
SITE pad
    SYMMETRY x y r90 ;
    CLASS pad ;
    SIZE 0.005 BY 199.500 ;
END pad 

SITE corner
    SYMMETRY x y r90 ;
    CLASS pad ;
    SIZE 199.500 BY 199.500 ;
END corner

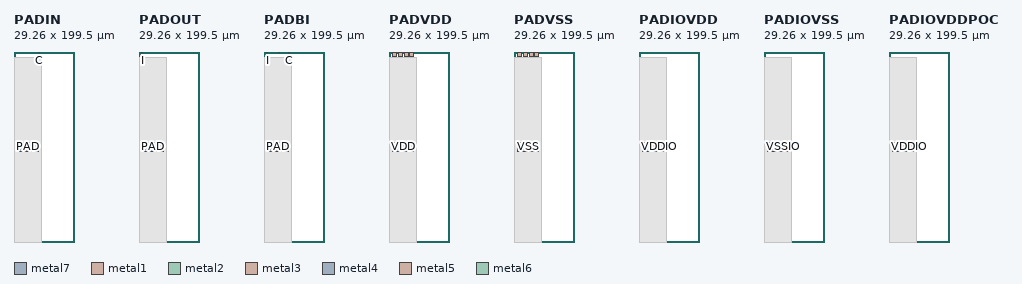
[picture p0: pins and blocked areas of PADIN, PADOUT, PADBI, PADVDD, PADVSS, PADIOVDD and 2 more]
MACRO PADIN
    CLASS PAD ;
    FOREIGN PADIN 0.000 0.000  ;
    ORIGIN 0.000 0.000 ;
    SIZE 29.260 BY 199.500 ;
    SYMMETRY x y r90 ;
    SITE pad ;
    PIN PAD
        DIRECTION INPUT ;
        PORT
        LAYER metal7 ;
        RECT  4.000 95 26.000 105 ;
        END
    END PAD
    PIN C
        DIRECTION OUTPUT ;
        PORT
        LAYER metal1 ;
        RECT  26 199.000 27 199.500 ;
        LAYER metal2 ;
        RECT  26 199.000 27 199.500 ;
        LAYER metal3 ;
        RECT  26 199.000 27 199.500 ;
        LAYER metal4 ;
        RECT  26 199.000 27 199.500 ;
        LAYER metal5 ;
        RECT  26 199.000 27 199.500 ;
        END
    END C
    OBS
        LAYER metal1 ;
        RECT  0.000 0.000 29.260 194.000 ;
        LAYER via1 ;
        RECT  0.000 0.000 29.260 194.000 ;
        LAYER metal2 ;
        RECT  0.000 0.000 29.260 194.000 ;
        LAYER via2 ;
        RECT  0.000 0.000 29.260 194.000 ;
        LAYER metal3 ;
        RECT  0.000 0.000 29.260 194.000 ;
        LAYER via3 ;
        RECT  0.000 0.000 29.260 194.000 ;
        LAYER metal4 ;
        RECT  0.000 0.000 29.260 194.000 ;
        LAYER via4 ;
        RECT  0.000 0.000 29.260 194.000 ;
        LAYER metal5 ;
        RECT  0.000 0.000 29.260 194.000 ;
        LAYER via5 ;
        RECT  0.000 0.000 29.260 194.000 ;
        LAYER metal6 ;
        RECT  0.000 0.000 29.260 194.000 ;
        LAYER via6 ;
        RECT  0.000 0.000 29.260 194.000 ;
    END
END PADIN

MACRO PADOUT
    CLASS PAD ;
    FOREIGN PADOUT 0.000 0.000  ;
    ORIGIN 0.000 0.000 ;
    SIZE 29.260 BY 199.500 ;
    SYMMETRY x y r90 ;
    SITE pad ;
    PIN PAD
        DIRECTION INOUT ;
        PORT
        LAYER metal7 ;
        RECT  4.000 95 26.000 105 ;
        END
    END PAD

    PIN I
        DIRECTION INPUT ;
        PORT
        LAYER metal1 ;
        RECT  3 199.000 4 199.500 ;
        LAYER metal2 ;
        RECT  3 199.000 4 199.500 ;
        LAYER metal3 ;
        RECT  3 199.000 4 199.500 ;
        LAYER metal4 ;
        RECT  3 199.000 4 199.500 ;
        LAYER metal5 ;
        RECT  3 199.000 4 199.500 ;
        LAYER metal6 ;
        RECT  3 199.000 4 199.500 ;
        END
    END I
    OBS
        LAYER metal1 ;
        RECT  0.000 0.000 29.260 194.000 ;
        LAYER via1 ;
        RECT  0.000 0.000 29.260 194.000 ;
        LAYER metal2 ;
        RECT  0.000 0.000 29.260 194.000 ;
        LAYER via2 ;
        RECT  0.000 0.000 29.260 194.000 ;
        LAYER metal3 ;
        RECT  0.000 0.000 29.260 194.000 ;
        LAYER via3 ;
        RECT  0.000 0.000 29.260 194.000 ;
        LAYER metal4 ;
        RECT  0.000 0.000 29.260 194.000 ;
        LAYER via4 ;
        RECT  0.000 0.000 29.260 194.000 ;
        LAYER metal5 ;
        RECT  0.000 0.000 29.260 194.000 ;
        LAYER via5 ;
        RECT  0.000 0.000 29.260 194.000 ;
        LAYER metal6 ;
        RECT  0.000 0.000 29.260 194.000 ;
        LAYER via6 ;
        RECT  0.000 0.000 29.260 194.000 ;
    END
END PADOUT

MACRO PADBI
    CLASS PAD ;
    FOREIGN PADBI 0.000 0.000  ;
    ORIGIN 0.000 0.000 ;
    SIZE 29.260 BY 199.500 ;
    SYMMETRY x y r90 ;
    SITE pad ;
    PIN PAD
        DIRECTION INOUT ;
        PORT
        LAYER metal7 ;
        RECT  4.000 95 26.000 105 ;
        END
    END PAD
    PIN C
        DIRECTION OUTPUT ;
        PORT
        LAYER metal1 ;
        RECT  26 199.000 27 199.500 ;
        LAYER metal2 ;
        RECT  26 199.000 27 199.500 ;
        LAYER metal3 ;
        RECT  26 199.000 27 199.500 ;
        LAYER metal4 ;
        RECT  26 199.000 27 199.500 ;
        LAYER metal5 ;
        RECT  26 199.000 27 199.500 ;
        LAYER metal6 ;
        RECT  26 199.000 27 199.500 ;
        END
    END C

    PIN OEN
        DIRECTION INPUT ;
        PORT
        LAYER metal1 ;
        RECT  15 199.090 16 199.500 ;
        LAYER metal2 ;
        RECT  15 199.000 16 199.500 ;
        LAYER metal3 ;
        RECT  15 199.000 16 199.500 ;
        LAYER metal4 ;
        RECT  15 199.000 16 199.500 ;
        LAYER metal5 ;
        RECT  15 199.000 16 199.500 ;
        LAYER metal6 ;
        RECT  15 199.000 16 199.500 ;
        END
    END OEN

    PIN I
        DIRECTION INPUT ;
        PORT
        LAYER metal1 ;
        RECT  3 199.000 4 199.500 ;
        LAYER metal2 ;
        RECT  3 199.000 4 199.500 ;
        LAYER metal3 ;
        RECT  3 199.000 4 199.500 ;
        LAYER metal4 ;
        RECT  3 199.000 4 199.500 ;
        LAYER metal5 ;
        RECT  3 199.000 4 199.500 ;
        LAYER metal6 ;
        RECT  3 199.000 4 199.500 ;
        END
    END I
    OBS
        LAYER metal1 ;
        RECT  0.000 0.000 29.260 194.000 ;
        LAYER via1 ;
        RECT  0.000 0.000 29.260 194.000 ;
        LAYER metal2 ;
        RECT  0.000 0.000 29.260 194.000 ;
        LAYER via2 ;
        RECT  0.000 0.000 29.260 194.000 ;
        LAYER metal3 ;
        RECT  0.000 0.000 29.260 194.000 ;
        LAYER via3 ;
        RECT  0.000 0.000 29.260 194.000 ;
        LAYER metal4 ;
        RECT  0.000 0.000 29.260 194.000 ;
        LAYER via4 ;
        RECT  0.000 0.000 29.260 194.000 ;
        LAYER metal5 ;
        RECT  0.000 0.000 29.260 194.000 ;
        LAYER via5 ;
        RECT  0.000 0.000 29.260 194.000 ;
        LAYER metal6 ;
        RECT  0.000 0.000 29.260 194.000 ;
        LAYER via6 ;
        RECT  0.000 0.000 29.260 194.000 ;
    END
END PADBI

MACRO PADVDD
    CLASS PAD ;
    FOREIGN PADVDD 0.000 0.000  ;
    ORIGIN 0.000 0.000 ;
    SIZE 29.260 BY 199.500 ;
    SYMMETRY x y r90 ;
    SITE pad ;
    PIN VDD
        DIRECTION INOUT ;
        USE power ;
        PORT
        CLASS CORE ;
        LAYER metal2 ;
        RECT  4.000 195.000 8.000 199.500 ;
        LAYER metal1 ;
        RECT  4.000 195.000 8.000 199.500 ;
        END
        PORT
        CLASS CORE ;
        LAYER metal2 ;
        RECT  10.000 195.000 14.000 199.500 ;
        LAYER metal1 ;
        RECT  10.000 195.000 14.000 199.500 ;
        END
        PORT
        CLASS CORE ;
        LAYER metal2 ;
        RECT  16.000 195.000 20.000 199.500 ;
        LAYER metal1 ;
        RECT  16.000 195.000 20.000 199.500 ;
        END
        PORT
        CLASS CORE ;
        LAYER metal2 ;
        RECT  22.000 195.000 26.000 199.500 ;
        LAYER metal1 ;
        RECT  22.000 195.000 26.000 199.500 ;
        END
        PORT
        LAYER metal7 ;
        RECT  4.000 95 26.000 105 ;
        END
    END VDD
    OBS
        LAYER metal1 ;
        RECT  0.000 0.000 29.260 194.000 ;
        LAYER via1 ;
        RECT  0.000 0.000 29.260 194.000 ;
        LAYER metal2 ;
        RECT  0.000 0.000 29.260 194.000 ;
        LAYER via2 ;
        RECT  0.000 0.000 29.260 194.000 ;
        LAYER metal3 ;
        RECT  0.000 0.000 29.260 194.000 ;
        LAYER via3 ;
        RECT  0.000 0.000 29.260 194.000 ;
        LAYER metal4 ;
        RECT  0.000 0.000 29.260 194.000 ;
        LAYER via4 ;
        RECT  0.000 0.000 29.260 194.000 ;
        LAYER metal5 ;
        RECT  0.000 0.000 29.260 194.000 ;
        LAYER via5 ;
        RECT  0.000 0.000 29.260 194.000 ;
        LAYER metal6 ;
        RECT  0.000 0.000 29.260 194.000 ;
        LAYER via6 ;
        RECT  0.000 0.000 29.260 194.000 ;
    END
END PADVDD

MACRO PADVSS
    CLASS PAD ;
    FOREIGN PADVSS 0.000 0.000  ;
    ORIGIN 0.000 0.000 ;
    SIZE 29.260 BY 199.500 ;
    SYMMETRY x y r90 ;
    SITE pad ;
    PIN VSS
        DIRECTION INOUT ;
        USE ground ;
        PORT
        CLASS CORE ;
        LAYER metal2 ;
        RECT  4.000 195.000 8.000 199.500 ;
        LAYER metal1 ;
        RECT  4.000 195.000 8.000 199.500 ;
        END
        PORT
        CLASS CORE ;
        LAYER metal2 ;
        RECT  10.000 195.000 14.000 199.500 ;
        LAYER metal1 ;
        RECT  10.000 195.000 14.000 199.500 ;
        END
        PORT
        CLASS CORE ;
        LAYER metal2 ;
        RECT  16.000 195.000 20.000 199.500 ;
        LAYER metal1 ;
        RECT  16.000 195.000 20.000 199.500 ;
        END
        PORT
        CLASS CORE ;
        LAYER metal2 ;
        RECT  22.000 195.000 26.000 199.500 ;
        LAYER metal1 ;
        RECT  22.000 195.000 26.000 199.500 ;
        END
        PORT
        LAYER metal7 ;
        RECT  4.000 95 26.000 105 ;
        END
    END VSS
    OBS
        LAYER metal1 ;
        RECT  0.000 0.000 29.260 194.000 ;
        LAYER via1 ;
        RECT  0.000 0.000 29.260 194.000 ;
        LAYER metal2 ;
        RECT  0.000 0.000 29.260 194.000 ;
        LAYER via2 ;
        RECT  0.000 0.000 29.260 194.000 ;
        LAYER metal3 ;
        RECT  0.000 0.000 29.260 194.000 ;
        LAYER via3 ;
        RECT  0.000 0.000 29.260 194.000 ;
        LAYER metal4 ;
        RECT  0.000 0.000 29.260 194.000 ;
        LAYER via4 ;
        RECT  0.000 0.000 29.260 194.000 ;
        LAYER metal5 ;
        RECT  0.000 0.000 29.260 194.000 ;
        LAYER via5 ;
        RECT  0.000 0.000 29.260 194.000 ;
        LAYER metal6 ;
        RECT  0.000 0.000 29.260 194.000 ;
        LAYER via6 ;
        RECT  0.000 0.000 29.260 194.000 ;
    END
END PADVSS

MACRO PADIOVDD
    CLASS PAD ;
    FOREIGN PADIOVDD 0.000 0.000  ;
    ORIGIN 0.000 0.000 ;
    SIZE 29.260 BY 199.500 ;
    SYMMETRY x y r90 ;
    SITE pad ;
    PIN VDDIO
        DIRECTION INOUT ;
        PORT
        LAYER metal7 ;
        RECT  4.000 95 26.000 105 ;
        END
    END VDDIO
    OBS
        LAYER metal1 ;
        RECT  0.000 0.000 29.260 194.000 ;
        LAYER via1 ;
        RECT  0.000 0.000 29.260 194.000 ;
        LAYER metal2 ;
        RECT  0.000 0.000 29.260 194.000 ;
        LAYER via2 ;
        RECT  0.000 0.000 29.260 194.000 ;
        LAYER metal3 ;
        RECT  0.000 0.000 29.260 194.000 ;
        LAYER via3 ;
        RECT  0.000 0.000 29.260 194.000 ;
        LAYER metal4 ;
        RECT  0.000 0.000 29.260 194.000 ;
        LAYER via4 ;
        RECT  0.000 0.000 29.260 194.000 ;
        LAYER metal5 ;
        RECT  0.000 0.000 29.260 194.000 ;
        LAYER via5 ;
        RECT  0.000 0.000 29.260 194.000 ;
        LAYER metal6 ;
        RECT  0.000 0.000 29.260 194.000 ;
        LAYER via6 ;
        RECT  0.000 0.000 29.260 194.000 ;
    END
END PADIOVDD

MACRO PADIOVSS
    CLASS PAD ;
    FOREIGN PADIOVSS 0.000 0.000  ;
    ORIGIN 0.000 0.000 ;
    SIZE 29.260 BY 199.500 ;
    SYMMETRY x y r90 ;
    SITE pad ;
    PIN VSSIO
        DIRECTION INOUT ;
        PORT
        LAYER metal7 ;
        RECT  4.000 95 26.000 105 ;
        END
    END VSSIO
    OBS
        LAYER metal1 ;
        RECT  0.000 0.000 29.260 194.000 ;
        LAYER via1 ;
        RECT  0.000 0.000 29.260 194.000 ;
        LAYER metal2 ;
        RECT  0.000 0.000 29.260 194.000 ;
        LAYER via2 ;
        RECT  0.000 0.000 29.260 194.000 ;
        LAYER metal3 ;
        RECT  0.000 0.000 29.260 194.000 ;
        LAYER via3 ;
        RECT  0.000 0.000 29.260 194.000 ;
        LAYER metal4 ;
        RECT  0.000 0.000 29.260 194.000 ;
        LAYER via4 ;
        RECT  0.000 0.000 29.260 194.000 ;
        LAYER metal5 ;
        RECT  0.000 0.000 29.260 194.000 ;
        LAYER via5 ;
        RECT  0.000 0.000 29.260 194.000 ;
        LAYER metal6 ;
        RECT  0.000 0.000 29.260 194.000 ;
        LAYER via6 ;
        RECT  0.000 0.000 29.260 194.000 ;
    END
END PADIOVSS

MACRO PADIOVDDPOC
    CLASS PAD ;
    FOREIGN PADIOVDDPOC 0.000 0.000  ;
    ORIGIN 0.000 0.000 ;
    SIZE 29.260 BY 199.500 ;
    SYMMETRY x y r90 ;
    SITE pad ;
    PIN VDDIO
        DIRECTION INOUT ;
        PORT
        LAYER metal7 ;
        RECT  4.000 95 26.000 105 ;
        END
    END VDDIO
    OBS
        LAYER metal1 ;
        RECT  0.000 0.000 29.260 194.000 ;
        LAYER via1 ;
        RECT  0.000 0.000 29.260 194.000 ;
        LAYER metal2 ;
        RECT  0.000 0.000 29.260 194.000 ;
        LAYER via2 ;
        RECT  0.000 0.000 29.260 194.000 ;
        LAYER metal3 ;
        RECT  0.000 0.000 29.260 194.000 ;
        LAYER via3 ;
        RECT  0.000 0.000 29.260 194.000 ;
        LAYER metal4 ;
        RECT  0.000 0.000 29.260 194.000 ;
        LAYER via4 ;
        RECT  0.000 0.000 29.260 194.000 ;
        LAYER metal5 ;
        RECT  0.000 0.000 29.260 194.000 ;
        LAYER via5 ;
        RECT  0.000 0.000 29.260 194.000 ;
        LAYER metal6 ;
        RECT  0.000 0.000 29.260 194.000 ;
        LAYER via6 ;
        RECT  0.000 0.000 29.260 194.000 ;
    END
END PADIOVDDPOC

MACRO PADCORNER
    CLASS ENDCAP BOTTOMLEFT ;
    FOREIGN PADCORNER 0.000 0.000  ;
    ORIGIN 0.000 0.000 ;
    SIZE 199.500 BY 199.500 ;
    SYMMETRY x y r90 ;
    SITE corner ;
    OBS
        LAYER metal1 ;
        RECT  0.000 0.000 194.000 194.000 ;
        LAYER via1 ;
        RECT  0.000 0.000 194.000 194.000 ;
        LAYER metal2 ;
        RECT  0.000 0.000 194.000 194.000 ;
        LAYER via2 ;
        RECT  0.000 0.000 194.000 194.000 ;
        LAYER metal3 ;
        RECT  0.000 0.000 194.000 194.000 ;
        LAYER via3 ;
        RECT  0.000 0.000 194.000 194.000 ;
        LAYER metal4 ;
        RECT  0.000 0.000 194.000 194.000 ;
        LAYER via4 ;
        RECT  0.000 0.000 194.000 194.000 ;
        LAYER metal5 ;
        RECT  0.000 0.000 194.000 194.000 ;
        LAYER via5 ;
        RECT  0.000 0.000 194.000 194.000 ;
        LAYER metal6 ;
        RECT  0.000 0.000 194.000 194.000 ;
        LAYER via6 ;
        RECT  0.000 0.000 194.000 194.000 ;
    END
END PADCORNER


MACRO PADFILLER0005
    CLASS PAD SPACER ;
    FOREIGN PADFILLER0005 0.000 0.000  ;
    ORIGIN 0.000 0.000 ;
    SIZE 0.005 BY 199.500 ;
    SYMMETRY x y r90 ;
    SITE pad ;
    OBS
        LAYER metal1 ;
        RECT  0.000 0.000 0.005 194.000 ;
        LAYER metal2 ;
        RECT  0.000 0.000 0.005 194.000 ;
        LAYER metal3 ;
        RECT  0.000 0.000 0.005 194.000 ;
        LAYER metal4 ;
        RECT  0.000 0.000 0.005 194.000 ;
        LAYER metal5 ;
        RECT  0.000 0.000 0.005 194.000 ;
        LAYER metal6 ;
        RECT  0.000 0.000 0.005 194.000 ;
    END
END PADFILLER0005

MACRO PADFILLER05
    CLASS PAD SPACER ;
    FOREIGN PADFILLER05 0.000 0.000  ;
    ORIGIN 0.000 0.000 ;
    SIZE 0.5 BY 199.500 ;
    SYMMETRY x y r90 ;
    SITE pad ;
    OBS
        LAYER metal1 ;
        RECT  0.000 0.000 0.5 194.000 ;
        LAYER metal2 ;
        RECT  0.000 0.000 0.5 194.000 ;
        LAYER metal3 ;
        RECT  0.000 0.000 0.5 194.000 ;
        LAYER metal4 ;
        RECT  0.000 0.000 0.5 194.000 ;
        LAYER metal5 ;
        RECT  0.000 0.000 0.5 194.000 ;
        LAYER metal6 ;
        RECT  0.000 0.000 0.5 194.000 ;
    END
END PADFILLER05

MACRO PADFILLER1
    CLASS PAD SPACER ;
    FOREIGN PADFILLER1 0.000 0.000  ;
    ORIGIN 0.000 0.000 ;
    SIZE 1 BY 199.500 ;
    SYMMETRY x y r90 ;
    SITE pad ;
    OBS
        LAYER metal1 ;
        RECT  0.000 0.000 1 194.000 ;
        LAYER metal2 ;
        RECT  0.000 0.000 1 194.000 ;
        LAYER metal3 ;
        RECT  0.000 0.000 1 194.000 ;
        LAYER metal4 ;
        RECT  0.000 0.000 1 194.000 ;
        LAYER metal5 ;
        RECT  0.000 0.000 1 194.000 ;
        LAYER metal6 ;
        RECT  0.000 0.000 1 194.000 ;
    END
END PADFILLER1

MACRO PADFILLER5
    CLASS PAD SPACER ;
    FOREIGN PADFILLER5 0.000 0.000  ;
    ORIGIN 0.000 0.000 ;
    SIZE 5 BY 199.500 ;
    SYMMETRY x y r90 ;
    SITE pad ;
    OBS
        LAYER metal1 ;
        RECT  0.000 0.000 5 194.000 ;
        LAYER metal2 ;
        RECT  0.000 0.000 5 194.000 ;
        LAYER metal3 ;
        RECT  0.000 0.000 5 194.000 ;
        LAYER metal4 ;
        RECT  0.000 0.000 5 194.000 ;
        LAYER metal5 ;
        RECT  0.000 0.000 5 194.000 ;
        LAYER metal6 ;
        RECT  0.000 0.000 5 194.000 ;
    END
END PADFILLER5

MACRO PADFILLER10
    CLASS PAD SPACER ;
    FOREIGN PADFILLER10 0.000 0.000  ;
    ORIGIN 0.000 0.000 ;
    SIZE 10 BY 199.500 ;
    SYMMETRY x y r90 ;
    SITE pad ;
    OBS
        LAYER metal1 ;
        RECT  0.000 0.000 10 194.000 ;
        LAYER metal2 ;
        RECT  0.000 0.000 10 194.000 ;
        LAYER metal3 ;
        RECT  0.000 0.000 10 194.000 ;
        LAYER metal4 ;
        RECT  0.000 0.000 10 194.000 ;
        LAYER metal5 ;
        RECT  0.000 0.000 10 194.000 ;
        LAYER metal6 ;
        RECT  0.000 0.000 10 194.000 ;
    END
END PADFILLER10

MACRO PADFILLER20
    CLASS PAD SPACER ;
    FOREIGN PADFILLER20 0.000 0.000  ;
    ORIGIN 0.000 0.000 ;
    SIZE 10 BY 199.500 ;
    SYMMETRY x y r90 ;
    SITE pad ;
    OBS
        LAYER metal1 ;
        RECT  0.000 0.000 20 194.000 ;
        LAYER metal2 ;
        RECT  0.000 0.000 20 194.000 ;
        LAYER metal3 ;
        RECT  0.000 0.000 20 194.000 ;
        LAYER metal4 ;
        RECT  0.000 0.000 20 194.000 ;
        LAYER metal5 ;
        RECT  0.000 0.000 20 194.000 ;
        LAYER metal6 ;
        RECT  0.000 0.000 20 194.000 ;
    END
END PADFILLER20

MACRO BONDINNER
    #CLASS BLOCK ;
    CLASS PAD ;
    FOREIGN BONDINNER 0.000 0.000  ;
    ORIGIN 0.000 0.000 ;
    SIZE 29.260 BY 100 ;
    SYMMETRY x y r90 ;
    OBS
        #LAYER metal7 ;
        #RECT  4.000 95.000 26.000 105.000 ;
        LAYER metal8 ;
        RECT  0.000 0.000 29.260 100.000 ; 
        LAYER metal9 ;
        RECT  -10.000 10.000 40.000 60.000 ; 
     END
END BONDINNER

MACRO BONDOUTER
    #CLASS BLOCK ;
    CLASS PAD ;
    FOREIGN BONDOUTER 0.000 0.000  ;
    ORIGIN 0.000 0.000 ;
    SIZE 29.260 BY 199.500 ;
    SYMMETRY x y r90 ;
    OBS
        #LAYER metal7 ;
        #RECT  4.000 95.000 26.000 105.000 ;
        LAYER metal8 ;
        RECT  0.000 0.000 29.260 199.500 ; 
        LAYER metal9 ;
        RECT  -10.000 140.000 40.000 190.000 ; 
     END
END BONDOUTER


END LIBRARY
